VERSION 5.4 ;
NAMESCASESENSITIVE ON ;
BUSBITCHARS "[]" ;
DIVIDERCHAR "/" ;
UNITS
  DATABASE MICRONS 2000 ;
END UNITS
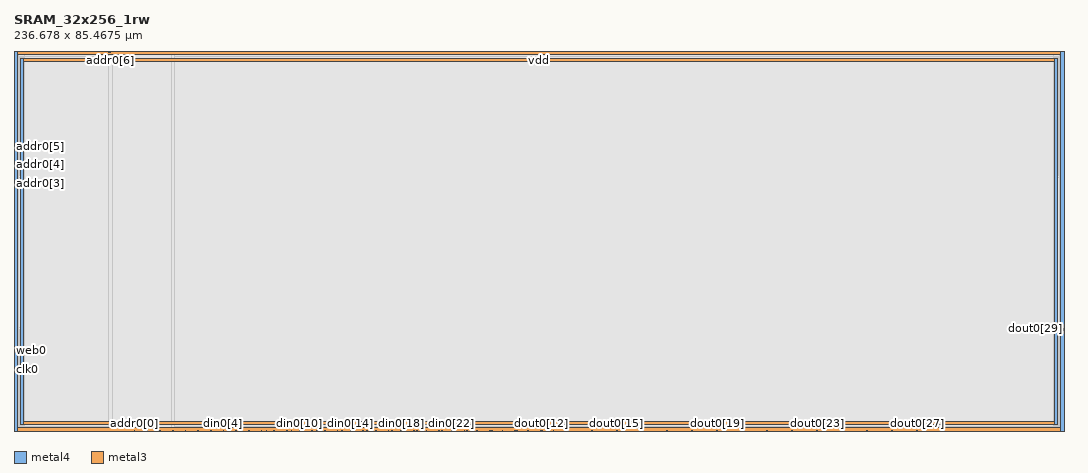
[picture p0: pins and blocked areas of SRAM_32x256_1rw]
MACRO SRAM_32x256_1rw
   CLASS BLOCK ;
   SIZE 236.6775 BY 85.4675 ;
   SYMMETRY X Y R90 ;
   PIN din0[0]
      DIRECTION INPUT ;
      PORT
         LAYER metal4 ;
         RECT  35.705 0.0 35.845 0.14 ;
      END
   END din0[0]
   PIN din0[1]
      DIRECTION INPUT ;
      PORT
         LAYER metal4 ;
         RECT  38.565 0.0 38.705 0.14 ;
      END
   END din0[1]
   PIN din0[2]
      DIRECTION INPUT ;
      PORT
         LAYER metal4 ;
         RECT  41.425 0.0 41.565 0.14 ;
      END
   END din0[2]
   PIN din0[3]
      DIRECTION INPUT ;
      PORT
         LAYER metal4 ;
         RECT  44.285 0.0 44.425 0.14 ;
      END
   END din0[3]
   PIN din0[4]
      DIRECTION INPUT ;
      PORT
         LAYER metal4 ;
         RECT  47.145 0.0 47.285 0.14 ;
      END
   END din0[4]
   PIN din0[5]
      DIRECTION INPUT ;
      PORT
         LAYER metal4 ;
         RECT  50.005 0.0 50.145 0.14 ;
      END
   END din0[5]
   PIN din0[6]
      DIRECTION INPUT ;
      PORT
         LAYER metal4 ;
         RECT  52.865 0.0 53.005 0.14 ;
      END
   END din0[6]
   PIN din0[7]
      DIRECTION INPUT ;
      PORT
         LAYER metal4 ;
         RECT  55.725 0.0 55.865 0.14 ;
      END
   END din0[7]
   PIN din0[8]
      DIRECTION INPUT ;
      PORT
         LAYER metal4 ;
         RECT  58.585 0.0 58.725 0.14 ;
      END
   END din0[8]
   PIN din0[9]
      DIRECTION INPUT ;
      PORT
         LAYER metal4 ;
         RECT  61.445 0.0 61.585 0.14 ;
      END
   END din0[9]
   PIN din0[10]
      DIRECTION INPUT ;
      PORT
         LAYER metal4 ;
         RECT  64.305 0.0 64.445 0.14 ;
      END
   END din0[10]
   PIN din0[11]
      DIRECTION INPUT ;
      PORT
         LAYER metal4 ;
         RECT  67.165 0.0 67.305 0.14 ;
      END
   END din0[11]
   PIN din0[12]
      DIRECTION INPUT ;
      PORT
         LAYER metal4 ;
         RECT  70.025 0.0 70.165 0.14 ;
      END
   END din0[12]
   PIN din0[13]
      DIRECTION INPUT ;
      PORT
         LAYER metal4 ;
         RECT  72.885 0.0 73.025 0.14 ;
      END
   END din0[13]
   PIN din0[14]
      DIRECTION INPUT ;
      PORT
         LAYER metal4 ;
         RECT  75.745 0.0 75.885 0.14 ;
      END
   END din0[14]
   PIN din0[15]
      DIRECTION INPUT ;
      PORT
         LAYER metal4 ;
         RECT  78.605 0.0 78.745 0.14 ;
      END
   END din0[15]
   PIN din0[16]
      DIRECTION INPUT ;
      PORT
         LAYER metal4 ;
         RECT  81.465 0.0 81.605 0.14 ;
      END
   END din0[16]
   PIN din0[17]
      DIRECTION INPUT ;
      PORT
         LAYER metal4 ;
         RECT  84.325 0.0 84.465 0.14 ;
      END
   END din0[17]
   PIN din0[18]
      DIRECTION INPUT ;
      PORT
         LAYER metal4 ;
         RECT  87.185 0.0 87.325 0.14 ;
      END
   END din0[18]
   PIN din0[19]
      DIRECTION INPUT ;
      PORT
         LAYER metal4 ;
         RECT  90.045 0.0 90.185 0.14 ;
      END
   END din0[19]
   PIN din0[20]
      DIRECTION INPUT ;
      PORT
         LAYER metal4 ;
         RECT  92.905 0.0 93.045 0.14 ;
      END
   END din0[20]
   PIN din0[21]
      DIRECTION INPUT ;
      PORT
         LAYER metal4 ;
         RECT  95.765 0.0 95.905 0.14 ;
      END
   END din0[21]
   PIN din0[22]
      DIRECTION INPUT ;
      PORT
         LAYER metal4 ;
         RECT  98.625 0.0 98.765 0.14 ;
      END
   END din0[22]
   PIN din0[23]
      DIRECTION INPUT ;
      PORT
         LAYER metal4 ;
         RECT  101.485 0.0 101.625 0.14 ;
      END
   END din0[23]
   PIN din0[24]
      DIRECTION INPUT ;
      PORT
         LAYER metal4 ;
         RECT  104.345 0.0 104.485 0.14 ;
      END
   END din0[24]
   PIN din0[25]
      DIRECTION INPUT ;
      PORT
         LAYER metal4 ;
         RECT  107.205 0.0 107.345 0.14 ;
      END
   END din0[25]
   PIN din0[26]
      DIRECTION INPUT ;
      PORT
         LAYER metal4 ;
         RECT  110.065 0.0 110.205 0.14 ;
      END
   END din0[26]
   PIN din0[27]
      DIRECTION INPUT ;
      PORT
         LAYER metal4 ;
         RECT  112.925 0.0 113.065 0.14 ;
      END
   END din0[27]
   PIN din0[28]
      DIRECTION INPUT ;
      PORT
         LAYER metal4 ;
         RECT  115.785 0.0 115.925 0.14 ;
      END
   END din0[28]
   PIN din0[29]
      DIRECTION INPUT ;
      PORT
         LAYER metal4 ;
         RECT  118.645 0.0 118.785 0.14 ;
      END
   END din0[29]
   PIN din0[30]
      DIRECTION INPUT ;
      PORT
         LAYER metal4 ;
         RECT  121.505 0.0 121.645 0.14 ;
      END
   END din0[30]
   PIN din0[31]
      DIRECTION INPUT ;
      PORT
         LAYER metal4 ;
         RECT  124.365 0.0 124.505 0.14 ;
      END
   END din0[31]
   PIN addr0[0]
      DIRECTION INPUT ;
      PORT
         LAYER metal4 ;
         RECT  27.125 0.0 27.265 0.14 ;
      END
   END addr0[0]
   PIN addr0[1]
      DIRECTION INPUT ;
      PORT
         LAYER metal4 ;
         RECT  29.985 0.0 30.125 0.14 ;
      END
   END addr0[1]
   PIN addr0[2]
      DIRECTION INPUT ;
      PORT
         LAYER metal4 ;
         RECT  32.845 0.0 32.985 0.14 ;
      END
   END addr0[2]
   PIN addr0[3]
      DIRECTION INPUT ;
      PORT
         LAYER metal3 ;
         RECT  0.0 57.36 0.14 57.5 ;
      END
   END addr0[3]
   PIN addr0[4]
      DIRECTION INPUT ;
      PORT
         LAYER metal3 ;
         RECT  0.0 60.09 0.14 60.23 ;
      END
   END addr0[4]
   PIN addr0[5]
      DIRECTION INPUT ;
      PORT
         LAYER metal3 ;
         RECT  0.0 62.3 0.14 62.44 ;
      END
   END addr0[5]
   PIN addr0[6]
      DIRECTION INPUT ;
      PORT
         LAYER metal4 ;
         RECT  21.6925 85.3275 21.8325 85.4675 ;
      END
   END addr0[6]
   PIN addr0[7]
      DIRECTION INPUT ;
      PORT
         LAYER metal4 ;
         RECT  21.4075 85.3275 21.5475 85.4675 ;
      END
   END addr0[7]
   PIN csb0
      DIRECTION INPUT ;
      PORT
         LAYER metal3 ;
         RECT  0.0 15.37 0.14 15.51 ;
      END
   END csb0
   PIN web0
      DIRECTION INPUT ;
      PORT
         LAYER metal3 ;
         RECT  0.0 18.1 0.14 18.24 ;
      END
   END web0
   PIN clk0
      DIRECTION INPUT ;
      PORT
         LAYER metal3 ;
         RECT  0.0 15.605 0.14 15.745 ;
      END
   END clk0
   PIN dout0[0]
      DIRECTION OUTPUT ;
      PORT
         LAYER metal4 ;
         RECT  51.24 0.0 51.38 0.14 ;
      END
   END dout0[0]
   PIN dout0[1]
      DIRECTION OUTPUT ;
      PORT
         LAYER metal4 ;
         RECT  56.88 0.0 57.02 0.14 ;
      END
   END dout0[1]
   PIN dout0[2]
      DIRECTION OUTPUT ;
      PORT
         LAYER metal4 ;
         RECT  62.52 0.0 62.66 0.14 ;
      END
   END dout0[2]
   PIN dout0[3]
      DIRECTION OUTPUT ;
      PORT
         LAYER metal4 ;
         RECT  68.16 0.0 68.3 0.14 ;
      END
   END dout0[3]
   PIN dout0[4]
      DIRECTION OUTPUT ;
      PORT
         LAYER metal4 ;
         RECT  73.8 0.0 73.94 0.14 ;
      END
   END dout0[4]
   PIN dout0[5]
      DIRECTION OUTPUT ;
      PORT
         LAYER metal4 ;
         RECT  79.44 0.0 79.58 0.14 ;
      END
   END dout0[5]
   PIN dout0[6]
      DIRECTION OUTPUT ;
      PORT
         LAYER metal4 ;
         RECT  85.08 0.0 85.22 0.14 ;
      END
   END dout0[6]
   PIN dout0[7]
      DIRECTION OUTPUT ;
      PORT
         LAYER metal4 ;
         RECT  90.72 0.0 90.86 0.14 ;
      END
   END dout0[7]
   PIN dout0[8]
      DIRECTION OUTPUT ;
      PORT
         LAYER metal4 ;
         RECT  96.36 0.0 96.5 0.14 ;
      END
   END dout0[8]
   PIN dout0[9]
      DIRECTION OUTPUT ;
      PORT
         LAYER metal4 ;
         RECT  102.0 0.0 102.14 0.14 ;
      END
   END dout0[9]
   PIN dout0[10]
      DIRECTION OUTPUT ;
      PORT
         LAYER metal4 ;
         RECT  107.64 0.0 107.78 0.14 ;
      END
   END dout0[10]
   PIN dout0[11]
      DIRECTION OUTPUT ;
      PORT
         LAYER metal4 ;
         RECT  113.28 0.0 113.42 0.14 ;
      END
   END dout0[11]
   PIN dout0[12]
      DIRECTION OUTPUT ;
      PORT
         LAYER metal4 ;
         RECT  118.93 0.0 119.07 0.14 ;
      END
   END dout0[12]
   PIN dout0[13]
      DIRECTION OUTPUT ;
      PORT
         LAYER metal4 ;
         RECT  124.65 0.0 124.79 0.14 ;
      END
   END dout0[13]
   PIN dout0[14]
      DIRECTION OUTPUT ;
      PORT
         LAYER metal4 ;
         RECT  130.2 0.0 130.34 0.14 ;
      END
   END dout0[14]
   PIN dout0[15]
      DIRECTION OUTPUT ;
      PORT
         LAYER metal4 ;
         RECT  135.84 0.0 135.98 0.14 ;
      END
   END dout0[15]
   PIN dout0[16]
      DIRECTION OUTPUT ;
      PORT
         LAYER metal4 ;
         RECT  141.48 0.0 141.62 0.14 ;
      END
   END dout0[16]
   PIN dout0[17]
      DIRECTION OUTPUT ;
      PORT
         LAYER metal4 ;
         RECT  147.12 0.0 147.26 0.14 ;
      END
   END dout0[17]
   PIN dout0[18]
      DIRECTION OUTPUT ;
      PORT
         LAYER metal4 ;
         RECT  152.76 0.0 152.9 0.14 ;
      END
   END dout0[18]
   PIN dout0[19]
      DIRECTION OUTPUT ;
      PORT
         LAYER metal4 ;
         RECT  158.4 0.0 158.54 0.14 ;
      END
   END dout0[19]
   PIN dout0[20]
      DIRECTION OUTPUT ;
      PORT
         LAYER metal4 ;
         RECT  164.04 0.0 164.18 0.14 ;
      END
   END dout0[20]
   PIN dout0[21]
      DIRECTION OUTPUT ;
      PORT
         LAYER metal4 ;
         RECT  169.68 0.0 169.82 0.14 ;
      END
   END dout0[21]
   PIN dout0[22]
      DIRECTION OUTPUT ;
      PORT
         LAYER metal4 ;
         RECT  175.32 0.0 175.46 0.14 ;
      END
   END dout0[22]
   PIN dout0[23]
      DIRECTION OUTPUT ;
      PORT
         LAYER metal4 ;
         RECT  180.96 0.0 181.1 0.14 ;
      END
   END dout0[23]
   PIN dout0[24]
      DIRECTION OUTPUT ;
      PORT
         LAYER metal4 ;
         RECT  186.6 0.0 186.74 0.14 ;
      END
   END dout0[24]
   PIN dout0[25]
      DIRECTION OUTPUT ;
      PORT
         LAYER metal4 ;
         RECT  192.24 0.0 192.38 0.14 ;
      END
   END dout0[25]
   PIN dout0[26]
      DIRECTION OUTPUT ;
      PORT
         LAYER metal4 ;
         RECT  197.88 0.0 198.02 0.14 ;
      END
   END dout0[26]
   PIN dout0[27]
      DIRECTION OUTPUT ;
      PORT
         LAYER metal4 ;
         RECT  203.52 0.0 203.66 0.14 ;
      END
   END dout0[27]
   PIN dout0[28]
      DIRECTION OUTPUT ;
      PORT
         LAYER metal4 ;
         RECT  209.16 0.0 209.3 0.14 ;
      END
   END dout0[28]
   PIN dout0[29]
      DIRECTION OUTPUT ;
      PORT
         LAYER metal3 ;
         RECT  236.5375 23.0125 236.6775 23.1525 ;
      END
   END dout0[29]
   PIN dout0[30]
      DIRECTION OUTPUT ;
      PORT
         LAYER metal3 ;
         RECT  236.5375 22.5425 236.6775 22.6825 ;
      END
   END dout0[30]
   PIN dout0[31]
      DIRECTION OUTPUT ;
      PORT
         LAYER metal3 ;
         RECT  236.5375 22.7775 236.6775 22.9175 ;
      END
   END dout0[31]
   PIN vdd
      DIRECTION INOUT ;
      USE POWER ; 
      SHAPE ABUTMENT ; 
      PORT
         LAYER metal3 ;
         RECT  0.0 0.0 236.6775 0.7 ;
         LAYER metal4 ;
         RECT  235.9775 0.0 236.6775 85.4675 ;
         LAYER metal3 ;
         RECT  0.0 84.7675 236.6775 85.4675 ;
         LAYER metal4 ;
         RECT  0.0 0.0 0.7 85.4675 ;
      END
   END vdd
   PIN gnd
      DIRECTION INOUT ;
      USE GROUND ; 
      SHAPE ABUTMENT ; 
      PORT
         LAYER metal4 ;
         RECT  1.4 1.4 2.1 84.0675 ;
         LAYER metal3 ;
         RECT  1.4 1.4 235.2775 2.1 ;
         LAYER metal4 ;
         RECT  234.5775 1.4 235.2775 84.0675 ;
         LAYER metal3 ;
         RECT  1.4 83.3675 235.2775 84.0675 ;
      END
   END gnd
   OBS
   LAYER  metal1 ;
      RECT  0.14 0.14 236.5375 85.3275 ;
   LAYER  metal2 ;
      RECT  0.14 0.14 236.5375 85.3275 ;
   LAYER  metal3 ;
      RECT  0.28 57.22 236.5375 57.64 ;
      RECT  0.14 57.64 0.28 59.95 ;
      RECT  0.14 60.37 0.28 62.16 ;
      RECT  0.14 18.38 0.28 57.22 ;
      RECT  0.14 15.885 0.28 17.96 ;
      RECT  0.28 22.8725 236.3975 23.2925 ;
      RECT  0.28 23.2925 236.3975 57.22 ;
      RECT  236.3975 23.2925 236.5375 57.22 ;
      RECT  0.14 0.84 0.28 15.23 ;
      RECT  236.3975 0.84 236.5375 22.4025 ;
      RECT  0.14 62.58 0.28 84.6275 ;
      RECT  0.28 0.84 1.26 1.26 ;
      RECT  0.28 1.26 1.26 2.24 ;
      RECT  0.28 2.24 1.26 22.8725 ;
      RECT  1.26 0.84 235.4175 1.26 ;
      RECT  1.26 2.24 235.4175 22.8725 ;
      RECT  235.4175 0.84 236.3975 1.26 ;
      RECT  235.4175 1.26 236.3975 2.24 ;
      RECT  235.4175 2.24 236.3975 22.8725 ;
      RECT  0.28 57.64 1.26 83.2275 ;
      RECT  0.28 83.2275 1.26 84.2075 ;
      RECT  0.28 84.2075 1.26 84.6275 ;
      RECT  1.26 57.64 235.4175 83.2275 ;
      RECT  1.26 84.2075 235.4175 84.6275 ;
      RECT  235.4175 57.64 236.5375 83.2275 ;
      RECT  235.4175 83.2275 236.5375 84.2075 ;
      RECT  235.4175 84.2075 236.5375 84.6275 ;
   LAYER  metal4 ;
      RECT  35.425 0.42 36.125 85.3275 ;
      RECT  36.125 0.14 38.285 0.42 ;
      RECT  38.985 0.14 41.145 0.42 ;
      RECT  41.845 0.14 44.005 0.42 ;
      RECT  44.705 0.14 46.865 0.42 ;
      RECT  47.565 0.14 49.725 0.42 ;
      RECT  53.285 0.14 55.445 0.42 ;
      RECT  59.005 0.14 61.165 0.42 ;
      RECT  64.725 0.14 66.885 0.42 ;
      RECT  70.445 0.14 72.605 0.42 ;
      RECT  76.165 0.14 78.325 0.42 ;
      RECT  81.885 0.14 84.045 0.42 ;
      RECT  87.605 0.14 89.765 0.42 ;
      RECT  93.325 0.14 95.485 0.42 ;
      RECT  99.045 0.14 101.205 0.42 ;
      RECT  104.765 0.14 106.925 0.42 ;
      RECT  110.485 0.14 112.645 0.42 ;
      RECT  116.205 0.14 118.365 0.42 ;
      RECT  121.925 0.14 124.085 0.42 ;
      RECT  27.545 0.14 29.705 0.42 ;
      RECT  30.405 0.14 32.565 0.42 ;
      RECT  33.265 0.14 35.425 0.42 ;
      RECT  21.4125 0.42 22.1125 85.0475 ;
      RECT  22.1125 0.42 35.425 85.0475 ;
      RECT  22.1125 85.0475 35.425 85.3275 ;
      RECT  50.425 0.14 50.96 0.42 ;
      RECT  51.66 0.14 52.585 0.42 ;
      RECT  56.145 0.14 56.6 0.42 ;
      RECT  57.3 0.14 58.305 0.42 ;
      RECT  61.865 0.14 62.24 0.42 ;
      RECT  62.94 0.14 64.025 0.42 ;
      RECT  67.585 0.14 67.88 0.42 ;
      RECT  68.58 0.14 69.745 0.42 ;
      RECT  73.305 0.14 73.52 0.42 ;
      RECT  74.22 0.14 75.465 0.42 ;
      RECT  79.025 0.14 79.16 0.42 ;
      RECT  79.86 0.14 81.185 0.42 ;
      RECT  84.745 0.14 84.8 0.42 ;
      RECT  85.5 0.14 86.905 0.42 ;
      RECT  91.14 0.14 92.625 0.42 ;
      RECT  96.78 0.14 98.345 0.42 ;
      RECT  102.42 0.14 104.065 0.42 ;
      RECT  108.06 0.14 109.785 0.42 ;
      RECT  113.7 0.14 115.505 0.42 ;
      RECT  119.35 0.14 121.225 0.42 ;
      RECT  125.07 0.14 129.92 0.42 ;
      RECT  130.62 0.14 135.56 0.42 ;
      RECT  136.26 0.14 141.2 0.42 ;
      RECT  141.9 0.14 146.84 0.42 ;
      RECT  147.54 0.14 152.48 0.42 ;
      RECT  153.18 0.14 158.12 0.42 ;
      RECT  158.82 0.14 163.76 0.42 ;
      RECT  164.46 0.14 169.4 0.42 ;
      RECT  170.1 0.14 175.04 0.42 ;
      RECT  175.74 0.14 180.68 0.42 ;
      RECT  181.38 0.14 186.32 0.42 ;
      RECT  187.02 0.14 191.96 0.42 ;
      RECT  192.66 0.14 197.6 0.42 ;
      RECT  198.3 0.14 203.24 0.42 ;
      RECT  203.94 0.14 208.88 0.42 ;
      RECT  209.58 0.14 235.6975 0.42 ;
      RECT  0.98 0.14 26.845 0.42 ;
      RECT  0.98 85.0475 21.1275 85.3275 ;
      RECT  0.98 0.42 1.12 1.12 ;
      RECT  0.98 1.12 1.12 84.3475 ;
      RECT  0.98 84.3475 1.12 85.0475 ;
      RECT  1.12 0.42 2.38 1.12 ;
      RECT  1.12 84.3475 2.38 85.0475 ;
      RECT  2.38 0.42 21.4125 1.12 ;
      RECT  2.38 1.12 21.4125 84.3475 ;
      RECT  2.38 84.3475 21.4125 85.0475 ;
      RECT  36.125 0.42 234.2975 1.12 ;
      RECT  36.125 1.12 234.2975 84.3475 ;
      RECT  36.125 84.3475 234.2975 85.3275 ;
      RECT  234.2975 0.42 235.5575 1.12 ;
      RECT  234.2975 84.3475 235.5575 85.3275 ;
      RECT  235.5575 0.42 235.6975 1.12 ;
      RECT  235.5575 1.12 235.6975 84.3475 ;
      RECT  235.5575 84.3475 235.6975 85.3275 ;
   END
END    SRAM_32x256_1rw
END    LIBRARY
